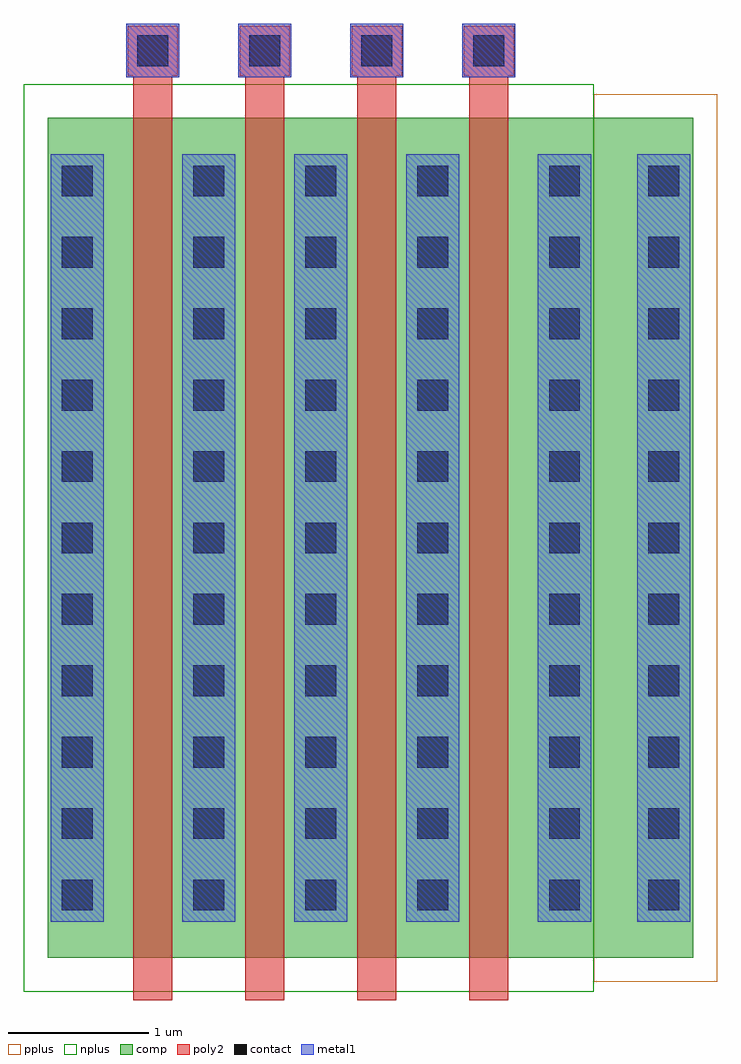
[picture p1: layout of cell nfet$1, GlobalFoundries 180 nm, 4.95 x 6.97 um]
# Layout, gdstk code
import gdstk
lib = gdstk.Library(unit=1e-6, precision=1e-09)
def R(c, l, rs):  # rectangles x0, y0, x1, y1
    for r in rs: c.add(gdstk.rectangle(r[:2], r[2:], *l))
def A(c, l, x, y, w, h, nx, ny, dx, dy):  # array of equal rectangles
    R(c, l, [(x+i*dx, y+j*dy, x+i*dx+w, y+j*dy+h) for i in range(nx) for j in range(ny)])
comp = (22, 0)
poly2 = (30, 0)
pplus = (31, 0)
nplus = (32, 0)
contact = (33, 0)
metal1 = (34, 0)

nfet_1 = lib.new_cell('nfet$1')
R(nfet_1, comp, [(-0.42,0,0,6), (0,0,3.06,6), (3.06,0,3.48,6), (3.48,0,4.19,6)])
A(nfet_1, poly2, 0.19, -0.3, 0.28, 6.6, 4, 1, 0.8, 0)
A(nfet_1, poly2, 0.15, 6.3, 0.36, 0.36, 4, 1, 0.8, 0)
R(nfet_1, pplus, [(3.48,-0.17,4.36,6.17)])
R(nfet_1, nplus, [(-0.59,-0.24,3.48,6.24)])
A(nfet_1, contact, -0.32, 0.34, 0.22, 0.22, 1, 11, 0, 0.51)
A(nfet_1, contact, 0.62, 0.34, 0.22, 0.22, 3, 11, 0.8, 0.51)
A(nfet_1, contact, 3.16, 0.34, 0.22, 0.22, 1, 11, 0, 0.51)
A(nfet_1, contact, 3.87, 0.34, 0.22, 0.22, 1, 11, 0, 0.51)
A(nfet_1, contact, 0.22, 6.37, 0.22, 0.22, 4, 1, 0.8, 0)
A(nfet_1, metal1, 0.54, 0.26, 0.38, 5.48, 3, 1, 0.8, 0)
A(nfet_1, metal1, 0.14, 6.289, 0.38, 0.382, 4, 1, 0.8, 0)
R(nfet_1, metal1, [(-0.4,0.26,-0.02,5.74), (3.08,0.26,3.46,5.74), (3.79,0.26,4.17,5.74)])

lib.write_gds('nfet_1.gds')
